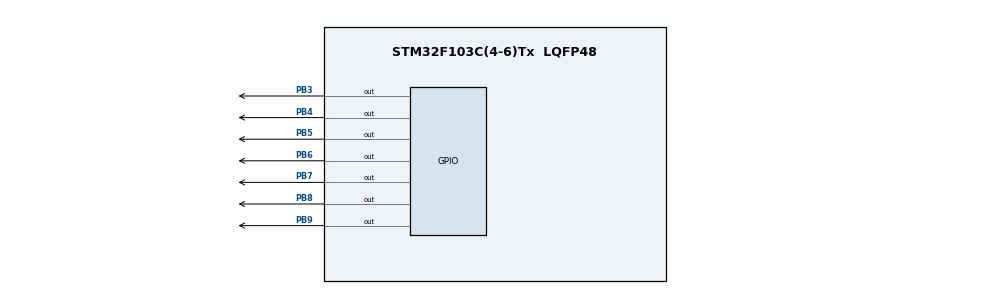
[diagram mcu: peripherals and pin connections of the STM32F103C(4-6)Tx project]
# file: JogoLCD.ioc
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Mcu.Family=STM32F1
Mcu.Name=STM32F103C(4-6)Tx
Mcu.Package=LQFP48
NVIC.PriorityGroup=NVIC_PRIORITYGROUP_4
PA13.Mode=Serial_Wire
PA13.Signal=SYS_JTMS-SWDIO
PA14.Mode=Serial_Wire
PA14.Signal=SYS_JTCK-SWCLK
PB3.Signal=GPIO_Output
PB4.Signal=GPIO_Output
PB5.Signal=GPIO_Output
PB6.Signal=GPIO_Output
PB7.Signal=GPIO_Output
PB8.Signal=GPIO_Output
PB9.Signal=GPIO_Output
ProjectManager.HeapSize=0x200
ProjectManager.StackSize=0x400
ProjectManager.TargetToolchain=STM32CubeIDE
RCC.APB1Freq_Value=8000000
RCC.APB2Freq_Value=8000000
board=custom

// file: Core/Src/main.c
/* USER CODE BEGIN Header */
/**
  ******************************************************************************
  * @file           : main.c
  * @brief          : Main program body
  ******************************************************************************
  * @attention
  *
  * <h2><center>&copy; Copyright (c) 2022 STMicroelectronics.
  * All rights reserved.</center></h2>
  *
  * This software component is licensed by ST under BSD 3-Clause license,
  * the "License"; You may not use this file except in compliance with the
  * License. You may obtain a copy of the License at:
  *                        opensource.org/licenses/BSD-3-Clause
  *
  ******************************************************************************
  */
/* USER CODE END Header */
#include "main.h"
/* USER CODE BEGIN Includes */
#include "lcd.h"
#include "bitmaps.h"
#include <stdbool.h>
#include <stdlib.h>
#include <string.h>

/* USER CODE END Includes */

/* USER CODE BEGIN PV */
static volatile bool buttonPressed = false;
/* USER CODE END PV */

void SystemClock_Config(void);
/* USER CODE BEGIN PFP */
static void MX_GPIO_Init(void);
/* USER CODE END PFP */

/* USER CODE BEGIN 0 */
/**
  * @brief  EXTI line detection callbacks.
  * @param  GPIO_Pin: Specifies the pins connected EXTI line
  * @retval None
  */
void HAL_GPIO_EXTI_Callback(uint16_t GPIO_Pin)
{
#if SIMULATE
  if(GPIO_Pin == GPIO_PIN_5){
	  buttonPressed = true;
  }
#else
  if(GPIO_Pin == GPIO_PIN_8){
  	  buttonPressed = true;
  }
#endif

}

/* USER CODE END 0 */

int main(void)
{
  /* USER CODE BEGIN 1 */

   byte runnerArea[16] = {32, 32, 32, 32, 32, 32, 32, 32, 32, 32, 32, 32, 32, 32, 32, 32};
   byte jump = 0;
   uint32_t currentMillisOb = 0, jumpTime = 0, previousMillis = 0;
   unsigned int score = 0, bestScore = 0;
   static bool freeze_score = false;
   const uint16_t speedOfScroller = 300;
   const uint16_t jumpLength = 500;
   uint8_t count = 0;

  /* USER CODE END 1 */

  /* MCU Configuration--------------------------------------------------------*/

  /* Reset of all peripherals, Initializes the Flash interface and the Systick. */
  HAL_Init();

  /* Configure the system clock */
  SystemClock_Config();

  /* Initialize all configured peripherals */
  MX_GPIO_Init();
  /* USER CODE BEGIN 2 */
  InitLCD();
  LCDCursorMode(0);

  // create a new character
  createChar(DINO, dino); // create dino
  createChar(CACTUS, cactus); // create cactus
  createChar(BIRD, bird); // create bird
  createChar(BLOCK, block); // create block

  DisplayStartScreen();
  HAL_Delay(3000);
  LCDClear();

  /* USER CODE END 2 */

  /* Infinite loop */
  /* USER CODE BEGIN WHILE */
  while (1)
  {
	  	count++;
	  	count = count % 15;
	   	currentMillisOb = HAL_GetTick();
		if (currentMillisOb - previousMillis >= speedOfScroller)
		{
			  previousMillis = currentMillisOb;

			  switch(count){
			  	  case CACTUS:
			  		  runnerArea[15] = CACTUS;
			  		  break;
			  	  case BIRD:
			  		  runnerArea[15] = BIRD;
			  		  break;
			  	  case BLOCK:
			  		  runnerArea[15] = BLOCK;
			  		  break;
			  	  default:
			  		  runnerArea[15] = SPACE;
			  		  break;
			  }
			  for (uint8_t i = 0; i <= 15; i++) {
				runnerArea[i] = runnerArea[i + 1];
			  }
			  if (freeze_score == false) {
				score++;
			  }
		}

		if(buttonPressed == true)
		{
			  if ((runnerArea[1] != SPACE) && (runnerArea[1] != CACTUS || runnerArea[1] != BIRD)) {
				runnerArea[1] = SPACE;
			  }
			  jump = DINO;
			  freeze_score = true;
			  jumpTime = HAL_GetTick();
			  buttonPressed = false;
#if SIMULATE
			  HAL_GPIO_TogglePin(GPIOC, GPIO_PIN_13);
#endif
		}
		if ((HAL_GetTick() - jumpTime) >= jumpLength)
		{
			  if ((runnerArea[1] == SPACE) || (runnerArea[1] == DINO)) {
				runnerArea[1] = DINO;
				jump = SPACE;
				freeze_score = false;
			  }
			  else {
				  buttonPressed = false;
				  ShowCrashScreen(score, &bestScore);
				  while(buttonPressed == false);// Keep in loop until button is pressed again
				  memset(runnerArea, SPACE, sizeof(runnerArea));// clear runner area
				  jump = SPACE;
				  score = 0;
			  }
		}

		UpdateLcd(runnerArea, jump);
		PrintScore(score);

    /* USER CODE END WHILE */

  }
}

void SystemClock_Config(void)
{
  RCC_OscInitTypeDef RCC_OscInitStruct = {0};
  RCC_ClkInitTypeDef RCC_ClkInitStruct = {0};

  /** Initializes the RCC Oscillators according to the specified parameters
  * in the RCC_OscInitTypeDef structure.
  */
  RCC_OscInitStruct.OscillatorType = RCC_OSCILLATORTYPE_HSI;
  RCC_OscInitStruct.HSIState = RCC_HSI_ON;
  RCC_OscInitStruct.HSICalibrationValue = RCC_HSICALIBRATION_DEFAULT;
  RCC_OscInitStruct.PLL.PLLState = RCC_PLL_NONE;
  if (HAL_RCC_OscConfig(&RCC_OscInitStruct) != HAL_OK)
  {
    Error_Handler();
  }
  /** Initializes the CPU, AHB and APB buses clocks
  */
  RCC_ClkInitStruct.ClockType = RCC_CLOCKTYPE_HCLK|RCC_CLOCKTYPE_SYSCLK
                              |RCC_CLOCKTYPE_PCLK1|RCC_CLOCKTYPE_PCLK2;
  RCC_ClkInitStruct.SYSCLKSource = RCC_SYSCLKSOURCE_HSI;
  RCC_ClkInitStruct.AHBCLKDivider = RCC_SYSCLK_DIV1;
  RCC_ClkInitStruct.APB1CLKDivider = RCC_HCLK_DIV1;
  RCC_ClkInitStruct.APB2CLKDivider = RCC_HCLK_DIV1;

  if (HAL_RCC_ClockConfig(&RCC_ClkInitStruct, FLASH_LATENCY_0) != HAL_OK)
  {
    Error_Handler();
  }
}

static void MX_GPIO_Init(void)
{
  GPIO_InitTypeDef GPIO_InitStruct = {0};

  /* GPIO Ports Clock Enable */
  __HAL_RCC_GPIOA_CLK_ENABLE();
  __HAL_RCC_GPIOB_CLK_ENABLE();

#if SIMULATE

  HAL_GPIO_WritePin(GPIOB, GPIO_PIN_3|GPIO_PIN_4|GPIO_PIN_5|GPIO_PIN_6|GPIO_PIN_0|GPIO_PIN_1, GPIO_PIN_RESET);
  HAL_GPIO_WritePin(GPIOC, GPIO_PIN_13, GPIO_PIN_RESET);

    /*Configure GPIO pins : PB3 PB4 PB5 PB6
                             PB7 PB8 PB9 */
  GPIO_InitStruct.Pin = GPIO_PIN_3|GPIO_PIN_4|GPIO_PIN_5|GPIO_PIN_6|GPIO_PIN_0|GPIO_PIN_1;

  GPIO_InitStruct.Mode = GPIO_MODE_OUTPUT_PP;
  GPIO_InitStruct.Pull = GPIO_NOPULL;
  GPIO_InitStruct.Speed = GPIO_SPEED_FREQ_HIGH;
  HAL_GPIO_Init(GPIOB, &GPIO_InitStruct);

  GPIO_InitStruct.Pin = GPIO_PIN_13;
  HAL_GPIO_Init(GPIOC, &GPIO_InitStruct);

	/*Configure GPIO pin : PA5 */
  GPIO_InitStruct.Pin = GPIO_PIN_5;
  GPIO_InitStruct.Mode = GPIO_MODE_IT_RISING;
  GPIO_InitStruct.Pull = GPIO_NOPULL;
  HAL_GPIO_Init(GPIOA, &GPIO_InitStruct);

#else

  /*Configure GPIO pin Output Level */
  HAL_GPIO_WritePin(GPIOB, GPIO_PIN_3|GPIO_PIN_4|GPIO_PIN_5|GPIO_PIN_6
                          |GPIO_PIN_7|GPIO_PIN_8|GPIO_PIN_9, GPIO_PIN_RESET);

  /*Configure GPIO pins : PB3 PB4 PB5 PB6
                           PB7 PB8 PB9 */
  GPIO_InitStruct.Pin = GPIO_PIN_3|GPIO_PIN_4|GPIO_PIN_5|GPIO_PIN_6
                          |GPIO_PIN_7|GPIO_PIN_8|GPIO_PIN_9;

  GPIO_InitStruct.Mode = GPIO_MODE_OUTPUT_PP;
  GPIO_InitStruct.Pull = GPIO_NOPULL;
  GPIO_InitStruct.Speed = GPIO_SPEED_FREQ_HIGH;
  HAL_GPIO_Init(GPIOB, &GPIO_InitStruct);

  /*Configure GPIO pin : PA8 */
  GPIO_InitStruct.Pin = GPIO_PIN_8;
  GPIO_InitStruct.Mode = GPIO_MODE_IT_FALLING;
  GPIO_InitStruct.Pull = GPIO_PULLUP;
  HAL_GPIO_Init(GPIOA, &GPIO_InitStruct);

#endif

  /* EXTI interrupt init*/
  HAL_NVIC_SetPriority(EXTI9_5_IRQn, 0, 0);
  HAL_NVIC_EnableIRQ(EXTI9_5_IRQn);

}

void Error_Handler(void)
{
  __disable_irq();
  while (1)
  {
  }
}

/************************ (C) COPYRIGHT STMicroelectronics *****END OF FILE****/
